VERSION 5.8 ;
BUSBITCHARS "[]" ;
DIVIDERCHAR "/" ;
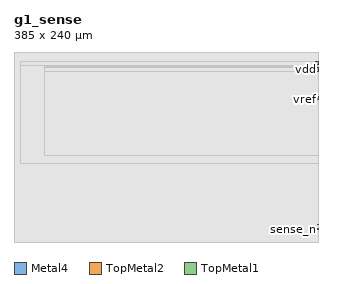
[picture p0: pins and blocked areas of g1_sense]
MACRO g1_sense
  CLASS BLOCK ;
  ORIGIN 0 0 ;
  FOREIGN g1_sense 0 0 ;
  SIZE 385.000 BY 240.000 ;
  SYMMETRY X Y R90 ;
  PIN iptat
    DIRECTION INOUT ;
    USE SIGNAL ;
    PORT
      LAYER Metal4 ;
      RECT 383.000 180.600 385.000 181.000 ;
    END
  END iptat
  PIN isense
    DIRECTION INOUT ;
    USE SIGNAL ;
    PORT
      LAYER Metal4 ;
      RECT 383.000 181.400 385.000 181.800 ;
    END
  END isense
  PIN sense_n
    DIRECTION INOUT ;
    USE SIGNAL ;
    PORT
      LAYER Metal4 ;
      RECT 383.000 15.500 385.000 16.500 ;
    END
  END sense_n
  PIN sense_p
    DIRECTION INOUT ;
    USE SIGNAL ;
    PORT
      LAYER Metal4 ;
      RECT 383.000 21.500 385.000 22.500 ;
    END
  END sense_p
  PIN vdd
    DIRECTION INOUT ;
    USE POWER ;
    PORT
      LAYER TopMetal2 ;
      RECT 381.000 216.000 385.000 220.000 ;
    END
  END vdd
  PIN vped
    DIRECTION INOUT ;
    USE SIGNAL ;
    PORT
      LAYER Metal4 ;
      RECT 383.000 182.200 385.000 182.600 ;
    END
  END vped
  PIN vref
    DIRECTION INOUT ;
    USE SIGNAL ;
    PORT
      LAYER Metal4 ;
      RECT 383.000 179.800 385.000 180.200 ;
    END
  END vref
  PIN vref_buf
    DIRECTION INOUT ;
    USE SIGNAL ;
    PORT
      LAYER Metal4 ;
      RECT 383.000 183.000 385.000 183.400 ;
    END
  END vref_buf
  PIN vss
    DIRECTION INOUT ;
    USE GROUND ;
    PORT
      LAYER TopMetal1 ;
      RECT 381.000 224.000 385.000 228.000 ;
    END
  END vss
  OBS
    LAYER Metal1 ;
      RECT 0.000 0.000 385.000 240.000 ;
    LAYER Metal2 ;
      RECT 0.000 0.000 385.000 240.000 ;
    LAYER Metal3 ;
      RECT 0.000 0.000 385.000 240.000 ;
    LAYER Metal4 ;
      RECT 0.000 0.000 385.000 15.000 ;
      RECT 0.000 15.000 383.000 17.000 ;
      RECT 0.000 17.000 385.000 21.000 ;
      RECT 0.000 21.000 383.000 23.000 ;
      RECT 0.000 23.000 385.000 179.300 ;
      RECT 0.000 179.300 383.000 183.800 ;
      RECT 0.000 183.800 385.000 240.000 ;
    LAYER Metal5 ;
      RECT 0.000 0.000 385.000 240.000 ;
    LAYER TopMetal1 ;
      RECT 8.020 98.920 385.000 223.500 ;
      RECT 8.020 223.500 381.000 228.000 ;
    LAYER TopMetal2 ;
      RECT 37.920 108.900 385.000 215.500 ;
      RECT 381.900 215.500 384.100 216.000 ;
      RECT 37.920 215.500 381.000 220.500 ;
      RECT 37.920 220.500 385.000 221.100 ;
  END
END g1_sense
END LIBRARY
